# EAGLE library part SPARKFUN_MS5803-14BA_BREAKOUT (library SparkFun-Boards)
SparkFun MSP5803-14BA Breakout I2C compatible pressure sensor breakout SparkFun Products: SparkFun MSP5803-14BA Breakout

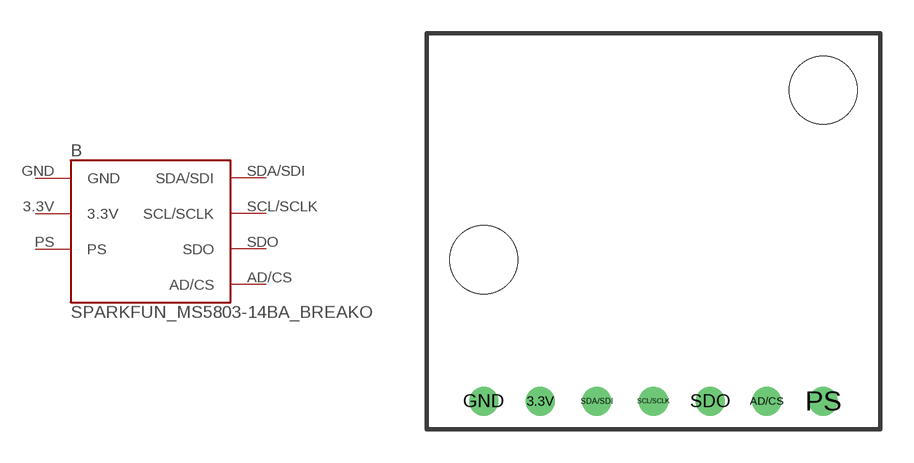
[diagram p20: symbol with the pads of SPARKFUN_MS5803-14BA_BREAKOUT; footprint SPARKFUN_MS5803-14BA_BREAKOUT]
Designator prefix B

## SPARKFUN_MS5803-14BA_BREAKOUT (SF_ID: SEN-12909; VALUE: Pressure Sensor)  [SPARKFUN_MS5803-14BA_BREAKOUT]
3.3V  3.3V
AD/CS  AD/CS
GND  GND
PS  PS
SCL/SCLK  SCL/SCLK
SDA/SDI  SDA/SDI
SDO  SDO

## Footprint SPARKFUN_MS5803-14BA_BREAKOUT (pad centres in mm)
SparkFun MS5803-14BA Breakout Specifications: Pin count:7 Pin pitch: 0.1" Area: 0.8x0.7" Example device(s): SPARKFUN_MS5803-14BA_BREAKOUT
drill 0.8: 3.3V 5.08,1.27; AD/CS 15.24,1.27; GND 2.54,1.27; PS 17.78,1.27; SCL/SCLK 10.16,1.27; SDA/SDI 7.62,1.27; SDO 12.7,1.27
hole 3.048 at 2.54,7.62
hole 3.048 at 17.78,15.24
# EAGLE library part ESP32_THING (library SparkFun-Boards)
SparkFun ESP32 Thing Board Pins, silkscreen, and logos matching the layout of the SparkFun ESP32 Thing Dimensions: 2.32" x 1.00"

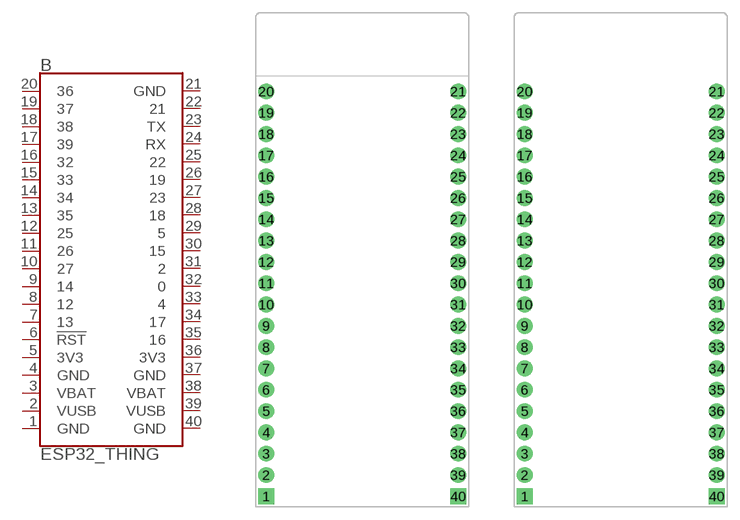
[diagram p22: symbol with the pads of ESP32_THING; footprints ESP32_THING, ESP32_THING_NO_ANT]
Designator prefix B

## ESP32_THING_W_ANT_KEEPOUT (SF_ID: DEV-13907)  [ESP32_THING]
1  GND
2  VUSB
3  VBAT
4  GND
5  3V3
6  !RST!
7  13
8  12
9  14
10  27
11  26
12  25
13  35
14  34
15  33
16  32
17  39
18  38
19  37
20  36
21  GND
22  21
23  TX
24  RX
25  22
26  19
27  23
28  18
29  5
30  15
31  2
32  0
33  4
34  17
35  16
36  3V3
37  GND
38  VBAT
39  VUSB
40  GND

## ESP32_THING_WO_ANT_KEEPOUT  [ESP32_THING_NO_ANT]
Pads as for ESP32_THING

## Footprint ESP32_THING (pad centres in mm)
SparkFun ESP32 Thing Board Pins, silkscreen, and logos matching the layout of the SparkFun ESP32 Thing Specifications: Pin count: 40 Area: 2.32" x 1.00"
drill 1.016 pad 1.88 square: 1 1.27,1.27; 40 24.13,1.27
drill 1.016 pad 1.88: 2 1.27,3.81; 3 1.27,6.35; 4 1.27,8.89; 5 1.27,11.43; 6 1.27,13.97; 7 1.27,16.51; 8 1.27,19.05; 9 1.27,21.59; 10 1.27,24.13; 11 1.27,26.67; 12 1.27,29.21; 13 1.27,31.75; 14 1.27,34.29; 15 1.27,36.83; 16 1.27,39.37; 17 1.27,41.91; 18 1.27,44.45; 19 1.27,46.99; 20 1.27,49.53; 21 24.13,49.53; 22 24.13,46.99; 23 24.13,44.45; 24 24.13,41.91; 25 24.13,39.37; 26 24.13,36.83; 27 24.13,34.29; 28 24.13,31.75; 29 24.13,29.21; 30 24.13,26.67; 31 24.13,24.13; 32 24.13,21.59; 33 24.13,19.05; 34 24.13,16.51; 35 24.13,13.97; 36 24.13,11.43; 37 24.13,8.89; 38 24.13,6.35; 39 24.13,3.81

## Footprint ESP32_THING_NO_ANT (pad centres in mm)
drill 1.016 pad 1.88 square: 1 1.27,1.27; 40 24.13,1.27
drill 1.016 pad 1.88: 2 1.27,3.81; 3 1.27,6.35; 4 1.27,8.89; 5 1.27,11.43; 6 1.27,13.97; 7 1.27,16.51; 8 1.27,19.05; 9 1.27,21.59; 10 1.27,24.13; 11 1.27,26.67; 12 1.27,29.21; 13 1.27,31.75; 14 1.27,34.29; 15 1.27,36.83; 16 1.27,39.37; 17 1.27,41.91; 18 1.27,44.45; 19 1.27,46.99; 20 1.27,49.53; 21 24.13,49.53; 22 24.13,46.99; 23 24.13,44.45; 24 24.13,41.91; 25 24.13,39.37; 26 24.13,36.83; 27 24.13,34.29; 28 24.13,31.75; 29 24.13,29.21; 30 24.13,26.67; 31 24.13,24.13; 32 24.13,21.59; 33 24.13,19.05; 34 24.13,16.51; 35 24.13,13.97; 36 24.13,11.43; 37 24.13,8.89; 38 24.13,6.35; 39 24.13,3.81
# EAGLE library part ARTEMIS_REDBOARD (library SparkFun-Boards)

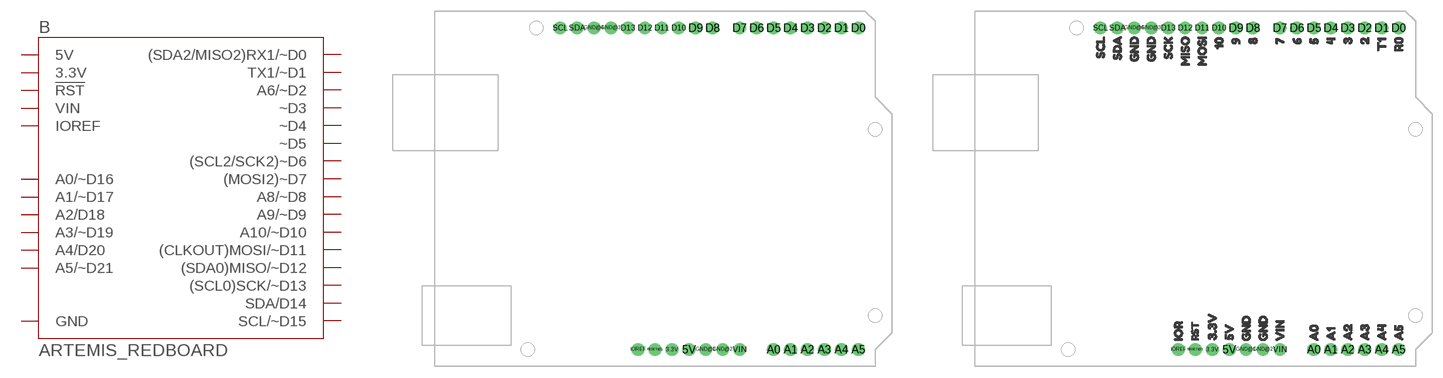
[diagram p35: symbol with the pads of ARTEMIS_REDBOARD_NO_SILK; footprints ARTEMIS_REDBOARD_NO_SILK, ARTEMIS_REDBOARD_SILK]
Designator prefix B

## ARTEMIS_REDBOARDNOSILK  [ARTEMIS_REDBOARD_NO_SILK]
3.3V  3.3V
5V  5V
A0  A0/~D16
A1  A1/~D17
A2  A2/D18
A3  A3/~D19
A4  A4/D20
A5  A5/~D21
D0  (SDA2/MISO2)RX1/~D0
D1  TX1/~D1
D2  A6/~D2
D3  ~D3
D4  ~D4
D5  ~D5
D6  (SCL2/SCK2)~D6
D7  (MOSI2)~D7
D8  A8/~D8
D9  A9/~D9
D10  A10/~D10
D11  (CLKOUT)MOSI/~D11
D12  (SDA0)MISO/~D12
D13  (SCL0)SCK/~D13
GND@1  GND
GND@2  GND
GND@3  GND
GND@4  GND
IOREF  IOREF
RESET@1  !RST
SCL  SCL/~D15
SDA  SDA/D14
VIN  VIN

## ARTEMIS_REDBOARD  [ARTEMIS_REDBOARD_SILK]
Pads as for ARTEMIS_REDBOARD_NO_SILK

## Footprint ARTEMIS_REDBOARD_NO_SILK (pad centres in mm)
drill 1.016 pad 1.93: 3.3V 1.27,-24.13; 5V 3.81,-24.13; A0 16.51,-24.13; A1 19.05,-24.13; A2 21.59,-24.13; A3 24.13,-24.13; A4 26.67,-24.13; A5 29.21,-24.13; D0 29.21,24.13; D1 26.67,24.13; D2 24.13,24.13; D3 21.59,24.13; D4 19.05,24.13; D5 16.51,24.13; D6 13.97,24.13; D7 11.43,24.13; D8 7.366,24.13; D9 4.826,24.13; D10 2.286,24.13; D11 -0.254,24.13; D12 -2.794,24.13; D13 -5.334,24.13; GND@1 6.35,-24.13; GND@2 8.89,-24.13; GND@3 -7.874,24.13; GND@4 -10.414,24.13; IOREF -3.81,-24.13; RESET@1 -1.27,-24.13; SCL -15.494,24.13; SDA -12.954,24.13; VIN 11.43,-24.13

## Footprint ARTEMIS_REDBOARD_SILK (pad centres in mm)
drill 1.016 pad 1.93: 3.3V 1.27,-24.13; 5V 3.81,-24.13; A0 16.51,-24.13; A1 19.05,-24.13; A2 21.59,-24.13; A3 24.13,-24.13; A4 26.67,-24.13; A5 29.21,-24.13; D0 29.21,24.13; D1 26.67,24.13; D2 24.13,24.13; D3 21.59,24.13; D4 19.05,24.13; D5 16.51,24.13; D6 13.97,24.13; D7 11.43,24.13; D8 7.366,24.13; D9 4.826,24.13; D10 2.286,24.13; D11 -0.254,24.13; D12 -2.794,24.13; D13 -5.334,24.13; GND@1 6.35,-24.13; GND@2 8.89,-24.13; GND@3 -7.874,24.13; GND@4 -10.414,24.13; IOREF -3.81,-24.13; RESET@1 -1.27,-24.13; SCL -15.494,24.13; SDA -12.954,24.13; VIN 11.43,-24.13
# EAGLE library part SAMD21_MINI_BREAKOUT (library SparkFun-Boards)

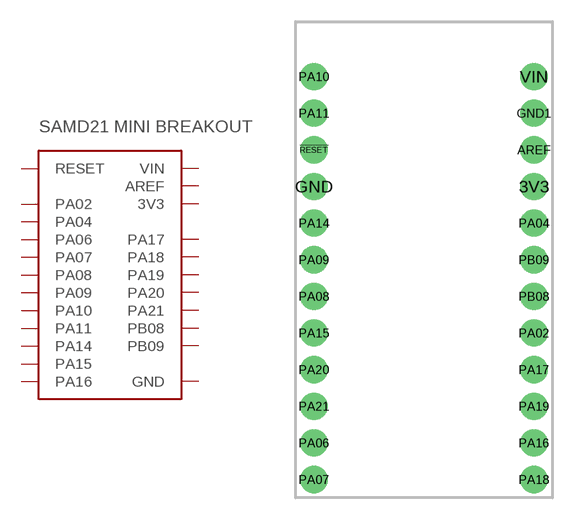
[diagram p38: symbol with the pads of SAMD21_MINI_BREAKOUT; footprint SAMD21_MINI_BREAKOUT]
Designator prefix -

## SAMD21_MINI_BREAKOUT  [SAMD21_MINI_BREAKOUT]
3V3  3V3
!RESET  RESET
AREF  AREF
GND  GND
GND1  GND
PA02  PA02
PA04  PA04
PA06  PA06
PA07  PA07
PA08  PA08
PA09  PA09
PA10  PA10
PA11  PA11
PA14  PA14
PA15  PA15
PA16  PA16
PA17  PA17
PA18  PA18
PA19  PA19
PA20  PA20
PA21  PA21
PB08  PB08
PB09  PB09
VIN  VIN

## Footprint SAMD21_MINI_BREAKOUT (pad centres in mm)
drill 1.016 pad 1.88: 3V3 16.51,21.59; !RESET 1.27,24.13; AREF 16.51,24.13; GND 1.27,21.59; GND1 16.51,26.67; PA02 16.51,11.43; PA04 16.51,19.05; PA06 1.27,3.81; PA07 1.27,1.27; PA08 1.27,13.97; PA09 1.27,16.51; PA10 1.27,29.21; PA11 1.27,26.67; PA14 1.27,19.05; PA15 1.27,11.43; PA16 16.51,3.81; PA17 16.51,8.89; PA18 16.51,1.27; PA19 16.51,6.35; PA20 1.27,8.89; PA21 1.27,6.35; PB08 16.51,13.97; PB09 16.51,16.51; VIN 16.51,29.21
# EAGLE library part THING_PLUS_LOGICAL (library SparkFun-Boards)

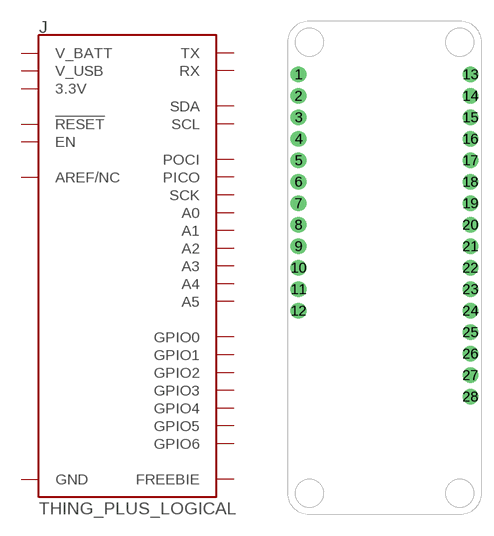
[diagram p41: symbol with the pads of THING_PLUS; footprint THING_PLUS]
Designator prefix J

## THING_PLUS_LOGICAL  [THING_PLUS]
1  SDA
2  SCL
3  GPIO6
4  GPIO5
5  GPIO4
6  GPIO3
7  GPIO2
8  GPIO1
9  GPIO0
10  V_USB
11  EN
12  V_BATT
13  FREEBIE
14  TX
15  RX
16  POCI
17  PICO
18  SCK
19  A5
20  A4
21  A3
22  A2
23  A1
24  A0
25  GND
26  AREF/NC
27  3.3V
28  !RESET

## Footprint THING_PLUS (pad centres in mm)
drill 1.016 pad 1.88: 1 1.27,52.07; 2 1.27,49.53; 3 1.27,46.99; 4 1.27,44.45; 5 1.27,41.91; 6 1.27,39.37; 7 1.27,36.83; 8 1.27,34.29; 9 1.27,31.75; 10 1.27,29.21; 11 1.27,26.67; 12 1.27,24.13; 13 21.59,52.07; 14 21.59,49.53; 15 21.59,46.99; 16 21.59,44.45; 17 21.59,41.91; 18 21.59,39.37; 19 21.59,36.83; 20 21.59,34.29; 21 21.59,31.75; 22 21.59,29.21; 23 21.59,26.67; 24 21.59,24.13; 25 21.59,21.59; 26 21.59,19.05; 27 21.59,16.51; 28 21.59,13.97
